# Generated by innovus_enablement/scripts/gen_fakeram.py: abstract 256x16 SRAM.
# Geometry is an assumption (see script header), not PDK data.
VERSION 5.8 ;
BUSBITCHARS "[]" ;
DIVIDERCHAR "/" ;

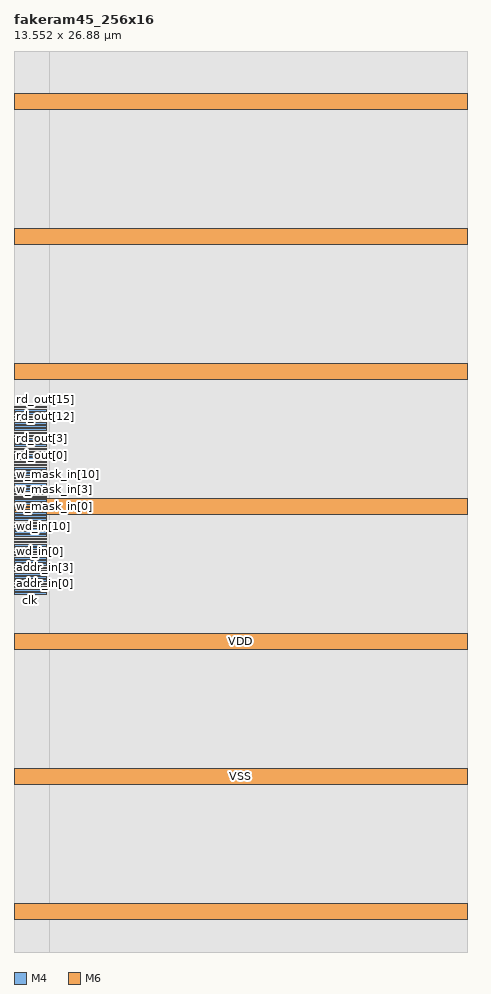
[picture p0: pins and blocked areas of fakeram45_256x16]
MACRO fakeram45_256x16
  CLASS BLOCK ;
  FOREIGN fakeram45_256x16 0 0 ;
  ORIGIN 0 0 ;
  SIZE 13.5520 BY 26.8800 ;
  SYMMETRY X Y R90 ;
  PIN clk
    DIRECTION INPUT ;
    USE CLOCK ;
    PORT
      LAYER M4 ;
        RECT 0 10.6800 0.9600 10.7280 ;
    END
  END clk
  PIN ce_in
    DIRECTION INPUT ;
    USE SIGNAL ;
    PORT
      LAYER M4 ;
        RECT 0 10.7760 0.9600 10.8240 ;
    END
  END ce_in
  PIN we_in
    DIRECTION INPUT ;
    USE SIGNAL ;
    PORT
      LAYER M4 ;
        RECT 0 10.8720 0.9600 10.9200 ;
    END
  END we_in
  PIN addr_in[0]
    DIRECTION INPUT ;
    USE SIGNAL ;
    PORT
      LAYER M4 ;
        RECT 0 10.9680 0.9600 11.0160 ;
    END
  END addr_in[0]
  PIN addr_in[1]
    DIRECTION INPUT ;
    USE SIGNAL ;
    PORT
      LAYER M4 ;
        RECT 0 11.0640 0.9600 11.1120 ;
    END
  END addr_in[1]
  PIN addr_in[2]
    DIRECTION INPUT ;
    USE SIGNAL ;
    PORT
      LAYER M4 ;
        RECT 0 11.1600 0.9600 11.2080 ;
    END
  END addr_in[2]
  PIN addr_in[3]
    DIRECTION INPUT ;
    USE SIGNAL ;
    PORT
      LAYER M4 ;
        RECT 0 11.2560 0.9600 11.3040 ;
    END
  END addr_in[3]
  PIN addr_in[4]
    DIRECTION INPUT ;
    USE SIGNAL ;
    PORT
      LAYER M4 ;
        RECT 0 11.3520 0.9600 11.4000 ;
    END
  END addr_in[4]
  PIN addr_in[5]
    DIRECTION INPUT ;
    USE SIGNAL ;
    PORT
      LAYER M4 ;
        RECT 0 11.4480 0.9600 11.4960 ;
    END
  END addr_in[5]
  PIN addr_in[6]
    DIRECTION INPUT ;
    USE SIGNAL ;
    PORT
      LAYER M4 ;
        RECT 0 11.5440 0.9600 11.5920 ;
    END
  END addr_in[6]
  PIN addr_in[7]
    DIRECTION INPUT ;
    USE SIGNAL ;
    PORT
      LAYER M4 ;
        RECT 0 11.6400 0.9600 11.6880 ;
    END
  END addr_in[7]
  PIN wd_in[0]
    DIRECTION INPUT ;
    USE SIGNAL ;
    PORT
      LAYER M4 ;
        RECT 0 11.7360 0.9600 11.7840 ;
    END
  END wd_in[0]
  PIN wd_in[1]
    DIRECTION INPUT ;
    USE SIGNAL ;
    PORT
      LAYER M4 ;
        RECT 0 11.8320 0.9600 11.8800 ;
    END
  END wd_in[1]
  PIN wd_in[2]
    DIRECTION INPUT ;
    USE SIGNAL ;
    PORT
      LAYER M4 ;
        RECT 0 11.9280 0.9600 11.9760 ;
    END
  END wd_in[2]
  PIN wd_in[3]
    DIRECTION INPUT ;
    USE SIGNAL ;
    PORT
      LAYER M4 ;
        RECT 0 12.0240 0.9600 12.0720 ;
    END
  END wd_in[3]
  PIN wd_in[4]
    DIRECTION INPUT ;
    USE SIGNAL ;
    PORT
      LAYER M4 ;
        RECT 0 12.1200 0.9600 12.1680 ;
    END
  END wd_in[4]
  PIN wd_in[5]
    DIRECTION INPUT ;
    USE SIGNAL ;
    PORT
      LAYER M4 ;
        RECT 0 12.2160 0.9600 12.2640 ;
    END
  END wd_in[5]
  PIN wd_in[6]
    DIRECTION INPUT ;
    USE SIGNAL ;
    PORT
      LAYER M4 ;
        RECT 0 12.3120 0.9600 12.3600 ;
    END
  END wd_in[6]
  PIN wd_in[7]
    DIRECTION INPUT ;
    USE SIGNAL ;
    PORT
      LAYER M4 ;
        RECT 0 12.4080 0.9600 12.4560 ;
    END
  END wd_in[7]
  PIN wd_in[8]
    DIRECTION INPUT ;
    USE SIGNAL ;
    PORT
      LAYER M4 ;
        RECT 0 12.5040 0.9600 12.5520 ;
    END
  END wd_in[8]
  PIN wd_in[9]
    DIRECTION INPUT ;
    USE SIGNAL ;
    PORT
      LAYER M4 ;
        RECT 0 12.6000 0.9600 12.6480 ;
    END
  END wd_in[9]
  PIN wd_in[10]
    DIRECTION INPUT ;
    USE SIGNAL ;
    PORT
      LAYER M4 ;
        RECT 0 12.6960 0.9600 12.7440 ;
    END
  END wd_in[10]
  PIN wd_in[11]
    DIRECTION INPUT ;
    USE SIGNAL ;
    PORT
      LAYER M4 ;
        RECT 0 12.7920 0.9600 12.8400 ;
    END
  END wd_in[11]
  PIN wd_in[12]
    DIRECTION INPUT ;
    USE SIGNAL ;
    PORT
      LAYER M4 ;
        RECT 0 12.8880 0.9600 12.9360 ;
    END
  END wd_in[12]
  PIN wd_in[13]
    DIRECTION INPUT ;
    USE SIGNAL ;
    PORT
      LAYER M4 ;
        RECT 0 12.9840 0.9600 13.0320 ;
    END
  END wd_in[13]
  PIN wd_in[14]
    DIRECTION INPUT ;
    USE SIGNAL ;
    PORT
      LAYER M4 ;
        RECT 0 13.0800 0.9600 13.1280 ;
    END
  END wd_in[14]
  PIN wd_in[15]
    DIRECTION INPUT ;
    USE SIGNAL ;
    PORT
      LAYER M4 ;
        RECT 0 13.1760 0.9600 13.2240 ;
    END
  END wd_in[15]
  PIN w_mask_in[0]
    DIRECTION INPUT ;
    USE SIGNAL ;
    PORT
      LAYER M4 ;
        RECT 0 13.2720 0.9600 13.3200 ;
    END
  END w_mask_in[0]
  PIN w_mask_in[1]
    DIRECTION INPUT ;
    USE SIGNAL ;
    PORT
      LAYER M4 ;
        RECT 0 13.3680 0.9600 13.4160 ;
    END
  END w_mask_in[1]
  PIN w_mask_in[2]
    DIRECTION INPUT ;
    USE SIGNAL ;
    PORT
      LAYER M4 ;
        RECT 0 13.4640 0.9600 13.5120 ;
    END
  END w_mask_in[2]
  PIN w_mask_in[3]
    DIRECTION INPUT ;
    USE SIGNAL ;
    PORT
      LAYER M4 ;
        RECT 0 13.5600 0.9600 13.6080 ;
    END
  END w_mask_in[3]
  PIN w_mask_in[4]
    DIRECTION INPUT ;
    USE SIGNAL ;
    PORT
      LAYER M4 ;
        RECT 0 13.6560 0.9600 13.7040 ;
    END
  END w_mask_in[4]
  PIN w_mask_in[5]
    DIRECTION INPUT ;
    USE SIGNAL ;
    PORT
      LAYER M4 ;
        RECT 0 13.7520 0.9600 13.8000 ;
    END
  END w_mask_in[5]
  PIN w_mask_in[6]
    DIRECTION INPUT ;
    USE SIGNAL ;
    PORT
      LAYER M4 ;
        RECT 0 13.8480 0.9600 13.8960 ;
    END
  END w_mask_in[6]
  PIN w_mask_in[7]
    DIRECTION INPUT ;
    USE SIGNAL ;
    PORT
      LAYER M4 ;
        RECT 0 13.9440 0.9600 13.9920 ;
    END
  END w_mask_in[7]
  PIN w_mask_in[8]
    DIRECTION INPUT ;
    USE SIGNAL ;
    PORT
      LAYER M4 ;
        RECT 0 14.0400 0.9600 14.0880 ;
    END
  END w_mask_in[8]
  PIN w_mask_in[9]
    DIRECTION INPUT ;
    USE SIGNAL ;
    PORT
      LAYER M4 ;
        RECT 0 14.1360 0.9600 14.1840 ;
    END
  END w_mask_in[9]
  PIN w_mask_in[10]
    DIRECTION INPUT ;
    USE SIGNAL ;
    PORT
      LAYER M4 ;
        RECT 0 14.2320 0.9600 14.2800 ;
    END
  END w_mask_in[10]
  PIN w_mask_in[11]
    DIRECTION INPUT ;
    USE SIGNAL ;
    PORT
      LAYER M4 ;
        RECT 0 14.3280 0.9600 14.3760 ;
    END
  END w_mask_in[11]
  PIN w_mask_in[12]
    DIRECTION INPUT ;
    USE SIGNAL ;
    PORT
      LAYER M4 ;
        RECT 0 14.4240 0.9600 14.4720 ;
    END
  END w_mask_in[12]
  PIN w_mask_in[13]
    DIRECTION INPUT ;
    USE SIGNAL ;
    PORT
      LAYER M4 ;
        RECT 0 14.5200 0.9600 14.5680 ;
    END
  END w_mask_in[13]
  PIN w_mask_in[14]
    DIRECTION INPUT ;
    USE SIGNAL ;
    PORT
      LAYER M4 ;
        RECT 0 14.6160 0.9600 14.6640 ;
    END
  END w_mask_in[14]
  PIN w_mask_in[15]
    DIRECTION INPUT ;
    USE SIGNAL ;
    PORT
      LAYER M4 ;
        RECT 0 14.7120 0.9600 14.7600 ;
    END
  END w_mask_in[15]
  PIN rd_out[0]
    DIRECTION OUTPUT ;
    USE SIGNAL ;
    PORT
      LAYER M4 ;
        RECT 0 14.8080 0.9600 14.8560 ;
    END
  END rd_out[0]
  PIN rd_out[1]
    DIRECTION OUTPUT ;
    USE SIGNAL ;
    PORT
      LAYER M4 ;
        RECT 0 14.9040 0.9600 14.9520 ;
    END
  END rd_out[1]
  PIN rd_out[2]
    DIRECTION OUTPUT ;
    USE SIGNAL ;
    PORT
      LAYER M4 ;
        RECT 0 15.0000 0.9600 15.0480 ;
    END
  END rd_out[2]
  PIN rd_out[3]
    DIRECTION OUTPUT ;
    USE SIGNAL ;
    PORT
      LAYER M4 ;
        RECT 0 15.0960 0.9600 15.1440 ;
    END
  END rd_out[3]
  PIN rd_out[4]
    DIRECTION OUTPUT ;
    USE SIGNAL ;
    PORT
      LAYER M4 ;
        RECT 0 15.1920 0.9600 15.2400 ;
    END
  END rd_out[4]
  PIN rd_out[5]
    DIRECTION OUTPUT ;
    USE SIGNAL ;
    PORT
      LAYER M4 ;
        RECT 0 15.2880 0.9600 15.3360 ;
    END
  END rd_out[5]
  PIN rd_out[6]
    DIRECTION OUTPUT ;
    USE SIGNAL ;
    PORT
      LAYER M4 ;
        RECT 0 15.3840 0.9600 15.4320 ;
    END
  END rd_out[6]
  PIN rd_out[7]
    DIRECTION OUTPUT ;
    USE SIGNAL ;
    PORT
      LAYER M4 ;
        RECT 0 15.4800 0.9600 15.5280 ;
    END
  END rd_out[7]
  PIN rd_out[8]
    DIRECTION OUTPUT ;
    USE SIGNAL ;
    PORT
      LAYER M4 ;
        RECT 0 15.5760 0.9600 15.6240 ;
    END
  END rd_out[8]
  PIN rd_out[9]
    DIRECTION OUTPUT ;
    USE SIGNAL ;
    PORT
      LAYER M4 ;
        RECT 0 15.6720 0.9600 15.7200 ;
    END
  END rd_out[9]
  PIN rd_out[10]
    DIRECTION OUTPUT ;
    USE SIGNAL ;
    PORT
      LAYER M4 ;
        RECT 0 15.7680 0.9600 15.8160 ;
    END
  END rd_out[10]
  PIN rd_out[11]
    DIRECTION OUTPUT ;
    USE SIGNAL ;
    PORT
      LAYER M4 ;
        RECT 0 15.8640 0.9600 15.9120 ;
    END
  END rd_out[11]
  PIN rd_out[12]
    DIRECTION OUTPUT ;
    USE SIGNAL ;
    PORT
      LAYER M4 ;
        RECT 0 15.9600 0.9600 16.0080 ;
    END
  END rd_out[12]
  PIN rd_out[13]
    DIRECTION OUTPUT ;
    USE SIGNAL ;
    PORT
      LAYER M4 ;
        RECT 0 16.0560 0.9600 16.1040 ;
    END
  END rd_out[13]
  PIN rd_out[14]
    DIRECTION OUTPUT ;
    USE SIGNAL ;
    PORT
      LAYER M4 ;
        RECT 0 16.1520 0.9600 16.2000 ;
    END
  END rd_out[14]
  PIN rd_out[15]
    DIRECTION OUTPUT ;
    USE SIGNAL ;
    PORT
      LAYER M4 ;
        RECT 0 16.2480 0.9600 16.2960 ;
    END
  END rd_out[15]
  PIN VDD
    DIRECTION INOUT ;
    USE POWER ;
    PORT
      LAYER M6 ;
        RECT 0 0.9600 13.5520 1.4400 ;
        RECT 0 9.0240 13.5520 9.5040 ;
        RECT 0 17.0880 13.5520 17.5680 ;
        RECT 0 25.1520 13.5520 25.6320 ;
    END
  END VDD
  PIN VSS
    DIRECTION INOUT ;
    USE GROUND ;
    PORT
      LAYER M6 ;
        RECT 0 4.9920 13.5520 5.4720 ;
        RECT 0 13.0560 13.5520 13.5360 ;
        RECT 0 21.1200 13.5520 21.6000 ;
    END
  END VSS
  OBS
    LAYER M0 ;
      RECT 0 0 13.5520 26.8800 ;
    LAYER M1 ;
      RECT 0 0 13.5520 26.8800 ;
    LAYER M2 ;
      RECT 0 0 13.5520 26.8800 ;
    LAYER M3 ;
      RECT 0 0 13.5520 26.8800 ;
    LAYER VIA0 ;
      RECT 0 0 13.5520 26.8800 ;
    LAYER VIA1 ;
      RECT 0 0 13.5520 26.8800 ;
    LAYER VIA2 ;
      RECT 0 0 13.5520 26.8800 ;
    LAYER VIA3 ;
      RECT 0 0 13.5520 26.8800 ;
    LAYER M4 ;
      RECT 1.0560 0 13.5520 26.8800 ;
  END
END fakeram45_256x16

END LIBRARY
